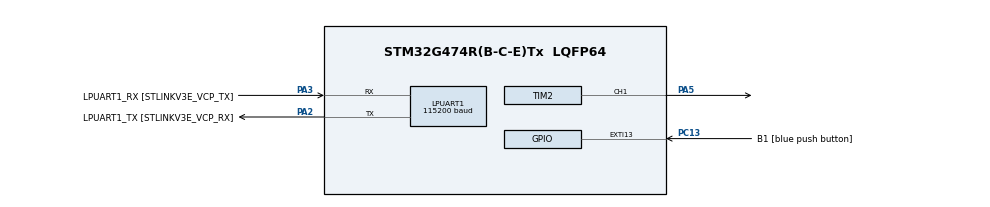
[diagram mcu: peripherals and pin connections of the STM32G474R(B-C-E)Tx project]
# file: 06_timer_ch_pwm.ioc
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LPUART1.BaudRate=115200
LPUART1.WordLength=UART_WORDLENGTH_8B
Mcu.Family=STM32G4
Mcu.Name=STM32G474R(B-C-E)Tx
Mcu.Package=LQFP64
NVIC.EXTI15_10_IRQn=true\:0\:0\:false\:false\:true\:true\:true\:true
NVIC.PriorityGroup=NVIC_PRIORITYGROUP_4
PA13.GPIO_Label=T_SWDIO
PA13.Mode=Serial_Wire
PA13.Signal=SYS_JTMS-SWDIO
PA14.GPIO_Label=T_SWCLK
PA14.Mode=Serial_Wire
PA14.Signal=SYS_JTCK-SWCLK
PA2.GPIO_Label=LPUART1_TX [STLINKV3E_VCP_RX]
PA2.Mode=Asynchronous
PA2.Signal=LPUART1_TX
PA3.GPIO_Label=LPUART1_RX [STLINKV3E_VCP_TX]
PA3.Mode=Asynchronous
PA3.Signal=LPUART1_RX
PA5.Signal=S_TIM2_CH1
PB3.GPIO_Label=T_SWO
PB3.Signal=SYS_JTDO-SWO
PC13.GPIO_Label=B1 [blue push button]
PC13.Signal=GPXTI13
PC14-OSC32_IN.Mode=LSE-External-Oscillator
PC14-OSC32_IN.Signal=RCC_OSC32_IN
PC15-OSC32_OUT.Mode=LSE-External-Oscillator
PC15-OSC32_OUT.Signal=RCC_OSC32_OUT
PF0-OSC_IN.Mode=HSE-External-Oscillator
PF0-OSC_IN.Signal=RCC_OSC_IN
PF1-OSC_OUT.Mode=HSE-External-Oscillator
PF1-OSC_OUT.Signal=RCC_OSC_OUT
ProjectManager.HeapSize=0x200
ProjectManager.StackSize=0x400
ProjectManager.TargetToolchain=STM32CubeIDE
RCC.ADC12Freq_Value=170000000
RCC.ADC345Freq_Value=170000000
RCC.AHBCLKDivider=RCC_SYSCLK_DIV2
RCC.AHBFreq_Value=85000000
RCC.APB1Freq_Value=85000000
RCC.APB1TimFreq_Value=85000000
RCC.APB2Freq_Value=85000000
RCC.APB2TimFreq_Value=85000000
RCC.CortexFreq_Value=85000000
RCC.EXTERNAL_CLOCK_VALUE=12288000
RCC.HCLKFreq_Value=85000000
RCC.HSE_VALUE=24000000
RCC.HSI48_VALUE=48000000
RCC.HSI_VALUE=16000000
RCC.PLLM=RCC_PLLM_DIV6
RCC.PLLN=85
RCC.PLLSourceVirtual=RCC_PLLSOURCE_HSE
RCC.RTCClockSelection=RCC_RTCCLKSOURCE_LSE
RCC.SYSCLKFreq_VALUE=170000000
RCC.SYSCLKSource=RCC_SYSCLKSOURCE_PLLCLK
RCC.USBFreq_Value=170000000
RCC.VCOOutputFreq_Value=340000000
SH.S_TIM2_CH1.0=TIM2_CH1,PWM Generation1 CH1
TIM2.AutoReloadPreload=TIM_AUTORELOAD_PRELOAD_ENABLE
TIM2.Channel-PWM\ Generation1\ CH1=TIM_CHANNEL_1
TIM2.PeriodNoDither=42500-1
TIM2.Prescaler=1
TIM2.PulseNoDither_1=0
VP_SYS_VS_DBSignals.Mode=DisableDeadBatterySignals
VP_TIM2_VS_ClockSourceINT.Mode=Internal
board=NUCLEO-G474RE

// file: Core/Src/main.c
/* USER CODE BEGIN Header */
/**
  ******************************************************************************
  * @file           : main.c
  * @brief          : Main program body
  ******************************************************************************
  * @attention
  *
  * <h2><center>&copy; Copyright (c) 2022 STMicroelectronics.
  * All rights reserved.</center></h2>
  *
  * This software component is licensed by ST under BSD 3-Clause license,
  * the "License"; You may not use this file except in compliance with the
  * License. You may obtain a copy of the License at:
  *                        opensource.org/licenses/BSD-3-Clause
  *
  ******************************************************************************
  */
/* USER CODE END Header */
#include "main.h"

 UART_HandleTypeDef hlpuart1;

TIM_HandleTypeDef htim2;

void SystemClock_Config(void);
static void MX_GPIO_Init(void);
static void MX_LPUART1_UART_Init(void);
static void MX_TIM2_Init(void);

int main(void)
{

  /* MCU Configuration--------------------------------------------------------*/

  /* Reset of all peripherals, Initializes the Flash interface and the Systick. */
  HAL_Init();

  /* Configure the system clock */
  SystemClock_Config();

  /* Initialize all configured peripherals */
  MX_GPIO_Init();
  MX_LPUART1_UART_Init();
  MX_TIM2_Init();

  /* Infinite loop */
  /* USER CODE BEGIN WHILE */
  if(HAL_TIM_PWM_Start(&htim2, TIM_CHANNEL_1) != HAL_OK)
  {
	  Error_Handler();
  }
  while (1)
  {
    /* USER CODE END WHILE */
	  __HAL_TIM_SET_COMPARE(&htim2,TIM_CHANNEL_1,21250);
  }
}

void SystemClock_Config(void)
{
  RCC_OscInitTypeDef RCC_OscInitStruct = {0};
  RCC_ClkInitTypeDef RCC_ClkInitStruct = {0};

  /** Configure the main internal regulator output voltage
  */
  HAL_PWREx_ControlVoltageScaling(PWR_REGULATOR_VOLTAGE_SCALE1_BOOST);

  /** Initializes the RCC Oscillators according to the specified parameters
  * in the RCC_OscInitTypeDef structure.
  */
  RCC_OscInitStruct.OscillatorType = RCC_OSCILLATORTYPE_HSE;
  RCC_OscInitStruct.HSEState = RCC_HSE_ON;
  RCC_OscInitStruct.PLL.PLLState = RCC_PLL_ON;
  RCC_OscInitStruct.PLL.PLLSource = RCC_PLLSOURCE_HSE;
  RCC_OscInitStruct.PLL.PLLM = RCC_PLLM_DIV6;
  RCC_OscInitStruct.PLL.PLLN = 85;
  RCC_OscInitStruct.PLL.PLLP = RCC_PLLP_DIV2;
  RCC_OscInitStruct.PLL.PLLQ = RCC_PLLQ_DIV2;
  RCC_OscInitStruct.PLL.PLLR = RCC_PLLR_DIV2;
  if (HAL_RCC_OscConfig(&RCC_OscInitStruct) != HAL_OK)
  {
    Error_Handler();
  }

  /** Initializes the CPU, AHB and APB buses clocks
  */
  RCC_ClkInitStruct.ClockType = RCC_CLOCKTYPE_HCLK|RCC_CLOCKTYPE_SYSCLK
                              |RCC_CLOCKTYPE_PCLK1|RCC_CLOCKTYPE_PCLK2;
  RCC_ClkInitStruct.SYSCLKSource = RCC_SYSCLKSOURCE_PLLCLK;
  RCC_ClkInitStruct.AHBCLKDivider = RCC_SYSCLK_DIV1;
  RCC_ClkInitStruct.APB1CLKDivider = RCC_HCLK_DIV1;
  RCC_ClkInitStruct.APB2CLKDivider = RCC_HCLK_DIV1;

  if (HAL_RCC_ClockConfig(&RCC_ClkInitStruct, FLASH_LATENCY_4) != HAL_OK)
  {
    Error_Handler();
  }
}

static void MX_LPUART1_UART_Init(void)
{

  hlpuart1.Instance = LPUART1;
  hlpuart1.Init.BaudRate = 115200;
  hlpuart1.Init.WordLength = UART_WORDLENGTH_8B;
  hlpuart1.Init.StopBits = UART_STOPBITS_1;
  hlpuart1.Init.Parity = UART_PARITY_NONE;
  hlpuart1.Init.Mode = UART_MODE_TX_RX;
  hlpuart1.Init.HwFlowCtl = UART_HWCONTROL_NONE;
  hlpuart1.Init.OneBitSampling = UART_ONE_BIT_SAMPLE_DISABLE;
  hlpuart1.Init.ClockPrescaler = UART_PRESCALER_DIV1;
  hlpuart1.AdvancedInit.AdvFeatureInit = UART_ADVFEATURE_NO_INIT;
  if (HAL_UART_Init(&hlpuart1) != HAL_OK)
  {
    Error_Handler();
  }
  if (HAL_UARTEx_SetTxFifoThreshold(&hlpuart1, UART_TXFIFO_THRESHOLD_1_8) != HAL_OK)
  {
    Error_Handler();
  }
  if (HAL_UARTEx_SetRxFifoThreshold(&hlpuart1, UART_RXFIFO_THRESHOLD_1_8) != HAL_OK)
  {
    Error_Handler();
  }
  if (HAL_UARTEx_DisableFifoMode(&hlpuart1) != HAL_OK)
  {
    Error_Handler();
  }

}

static void MX_TIM2_Init(void)
{

  TIM_ClockConfigTypeDef sClockSourceConfig = {0};
  TIM_MasterConfigTypeDef sMasterConfig = {0};
  TIM_OC_InitTypeDef sConfigOC = {0};

  htim2.Instance = TIM2;
  htim2.Init.Prescaler = 1;
  htim2.Init.CounterMode = TIM_COUNTERMODE_UP;
  htim2.Init.Period = 42499;
  htim2.Init.ClockDivision = TIM_CLOCKDIVISION_DIV1;
  htim2.Init.AutoReloadPreload = TIM_AUTORELOAD_PRELOAD_ENABLE;
  if (HAL_TIM_Base_Init(&htim2) != HAL_OK)
  {
    Error_Handler();
  }
  sClockSourceConfig.ClockSource = TIM_CLOCKSOURCE_INTERNAL;
  if (HAL_TIM_ConfigClockSource(&htim2, &sClockSourceConfig) != HAL_OK)
  {
    Error_Handler();
  }
  if (HAL_TIM_PWM_Init(&htim2) != HAL_OK)
  {
    Error_Handler();
  }
  sMasterConfig.MasterOutputTrigger = TIM_TRGO_RESET;
  sMasterConfig.MasterSlaveMode = TIM_MASTERSLAVEMODE_DISABLE;
  if (HAL_TIMEx_MasterConfigSynchronization(&htim2, &sMasterConfig) != HAL_OK)
  {
    Error_Handler();
  }
  sConfigOC.OCMode = TIM_OCMODE_PWM1;
  sConfigOC.Pulse = 0;
  sConfigOC.OCPolarity = TIM_OCPOLARITY_HIGH;
  sConfigOC.OCFastMode = TIM_OCFAST_DISABLE;
  if (HAL_TIM_PWM_ConfigChannel(&htim2, &sConfigOC, TIM_CHANNEL_1) != HAL_OK)
  {
    Error_Handler();
  }
  HAL_TIM_MspPostInit(&htim2);

}

static void MX_GPIO_Init(void)
{
  GPIO_InitTypeDef GPIO_InitStruct = {0};

  /* GPIO Ports Clock Enable */
  __HAL_RCC_GPIOC_CLK_ENABLE();
  __HAL_RCC_GPIOF_CLK_ENABLE();
  __HAL_RCC_GPIOA_CLK_ENABLE();
  __HAL_RCC_GPIOB_CLK_ENABLE();

  /*Configure GPIO pin : B1_Pin */
  GPIO_InitStruct.Pin = B1_Pin;
  GPIO_InitStruct.Mode = GPIO_MODE_IT_RISING;
  GPIO_InitStruct.Pull = GPIO_NOPULL;
  HAL_GPIO_Init(B1_GPIO_Port, &GPIO_InitStruct);

  /* EXTI interrupt init*/
  HAL_NVIC_SetPriority(EXTI15_10_IRQn, 0, 0);
  HAL_NVIC_EnableIRQ(EXTI15_10_IRQn);

}

void Error_Handler(void)
{
  /* USER CODE BEGIN Error_Handler_Debug */
  /* User can add his own implementation to report the HAL error return state */
	while(1);
  /* USER CODE END Error_Handler_Debug */
}
